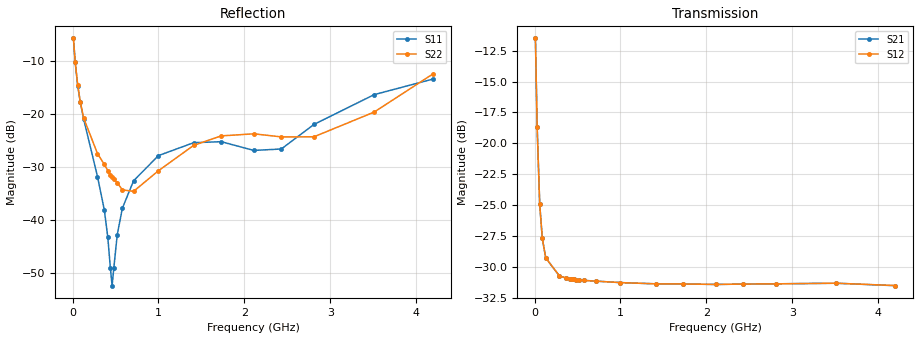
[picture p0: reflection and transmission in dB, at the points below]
! Integrated Device Technology
! Corporate Headquarters
! 6024 Silver Creek Valley Road
! San Jose, CA 95138  USA
! Phone:  1-408-284-8200
! Toll Free:  1-800-223-1366
! Webpage:  http://www.idt.com/
! Timing and RF Division
! 515 Groton Road, Suite 102
! Westford, MA 01886-6024
! Device:  F1950
! Description: 7-bit 0.25 dB Digital Step Attenuator
! Frequency:  150.0 -  4000.00 MHz
! Package:  4x4 mm Thin QFN Plastic Package: 24 pin
! Ports:  2 RF, 12 DC
!  Pin  1  = D0
!  Pin  2  = VDD
!  Pin  3  = Vmode
!  Pin  4  = GND
!  Pin  5  = RF1  =  Port 1
!  Pin  6  = GND
!  Pin  7  = GND
!  Pin  8  = GND
!  Pin  9  = GND
!  Pin 10  = GND
!  Pin 11  = GND
!  Pin 12  = GND
!  Pin 13  = GND
!  Pin 14  = RF2  =  Port 2
!  Pin 15  = GND
!  Pin 16  = LE
!  Pin 17  = CLK
!  Pin 18  = DATE
!  Pin 19  = D6
!  Pin 20  = D5
!  Pin 21  = D4
!  Pin 22  = D3
!  Pin 23  = D2
!  Pin 24  = D1
! State:  121
! Atten State:  30.25 dB
! Voltage:  +5.00 Volts
! Current:  Not Measured mA
! Data:  The device was measured on a the F195X evaluation board which has
!  individual transmission lines to the RF pins.  Data was collected
!  using a calibrated network analyzer.  The evaluation board was
!  de-embedded using a TRL calibration technique.
!  The reference plane is the edge of the package pin.
! Misc:  Board 2019
!  Action Tracker AT0250
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# GHz S dB R 50
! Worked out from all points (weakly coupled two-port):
!   420 points, 10 MHz to 4.2 GHz, reference 50 ohm
!   highest |S21| = -11.51 dB at 10 MHz (marker M1); lowest = -31.5 dB at 4.2 GHz (marker M2)
!   lowest |S11| = -52.4 dB at 460 MHz (marker M3), VSWR 1.00, Z = 49.8 - j0.109 ohm
!   |S11| at or under -10 dB: 28.84 MHz to end of sweep
!   |S22| runs from -35.0 to -5.8 dB; largest |S21 - S12| = 7.7e-05
!   S11 on the Smith chart (normalised r, x): 10 MHz: 2.06, -1.34; 30 MHz: 1.26, -0.68; 60 MHz: 1.10, -0.37; 290 MHz: 1.01, -0.05; 4.2 GHz: 0.68, +0.17
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0.01  -5.82 -28.0  -11.51 -39.8  -11.51 -39.8  -5.82 -28.9
0.03  -10.24 -52.6  -18.66 -66.1  -18.66 -66.1  -10.21 -53.8
0.06  -14.80 -65.0  -24.94 -61.0  -24.94 -61.0  -14.61 -66.3
0.09  -17.86 -70.5  -27.68 -49.8  -27.68 -49.9  -17.84 -70.6
0.13  -21.11 -73.0  -29.26 -38.7  -29.26 -38.7  -20.89 -74.1
0.29  -31.86 -73.9  -30.73 -20.9  -30.72 -21.0  -27.53 -83.1
0.37  -38.20 -73.7  -30.90 -17.7  -30.90 -17.8  -29.59 -87.1
0.41  -43.30 -84.3  -30.95 -16.7  -30.95 -16.7  -30.73 -89.1
0.44  -49.11 -106.9  -30.99 -16.1  -30.98 -16.1  -31.55 -93.2
0.46  -52.43 -152.7  -31.00 -15.7  -31.00 -15.7  -31.95 -96.6
0.48  -49.09 162.9  -31.02 -15.4  -31.02 -15.4  -32.26 -99.5
0.52  -42.80 145.0  -31.04 -14.8  -31.04 -14.8  -33.05 -103.1
0.58  -37.82 137.8  -31.08 -14.3  -31.09 -14.3  -34.37 -115.6
0.71  -32.66 139.2  -31.14 -13.6  -31.14 -13.6  -34.65 -140.8
1  -27.91 148.2  -31.26 -13.5  -31.26 -13.6  -30.76 178.5
1.41  -25.48 162.8  -31.36 -14.6  -31.36 -14.7  -25.98 160.0
1.73  -25.29 167.9  -31.37 -15.7  -31.37 -15.8  -24.20 151.6
2.11  -26.94 157.6  -31.41 -18.1  -31.41 -18.1  -23.81 141.6
2.43  -26.67 126.2  -31.38 -19.4  -31.38 -19.5  -24.39 130.8
2.81  -22.04 105.4  -31.36 -21.9  -31.36 -22.0  -24.37 115.4
3.51  -16.43 117.4  -31.31 -26.0  -31.31 -26.1  -19.72 112.8
4.2  -13.47 145.6  -31.51 -27.5  -31.50 -27.5  -12.47 127.0
